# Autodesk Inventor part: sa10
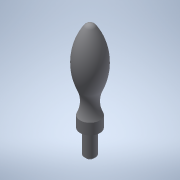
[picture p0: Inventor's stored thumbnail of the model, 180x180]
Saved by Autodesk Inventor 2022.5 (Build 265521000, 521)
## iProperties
Created: 2016-12
Part Number: sa10
Material: 一般
Document SubType Name: Modeling
Designer: imaocorp
Density: 1 g/cm^3
Appearance: 既定
Author: imaocorp
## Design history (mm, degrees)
node "sa10.x_t1"
node "sa10"
node "Base1"
